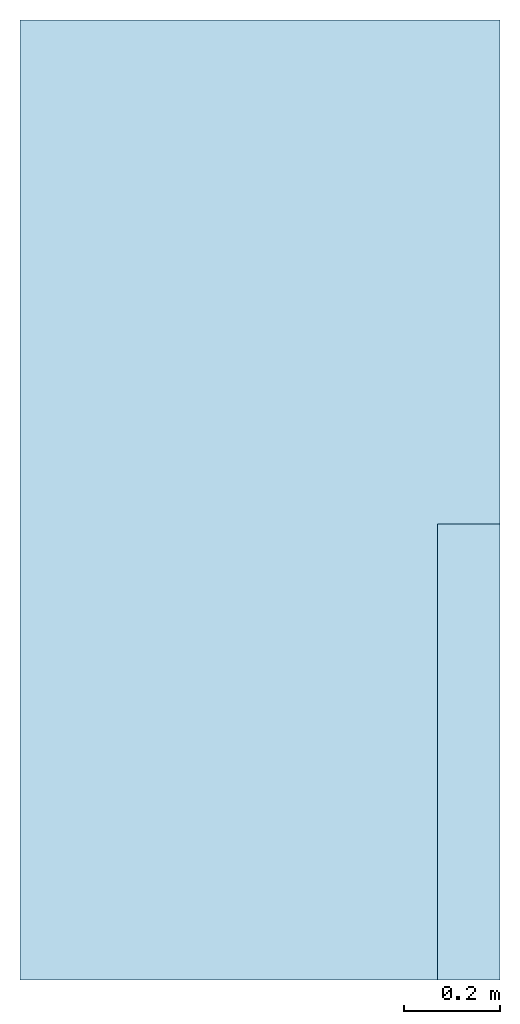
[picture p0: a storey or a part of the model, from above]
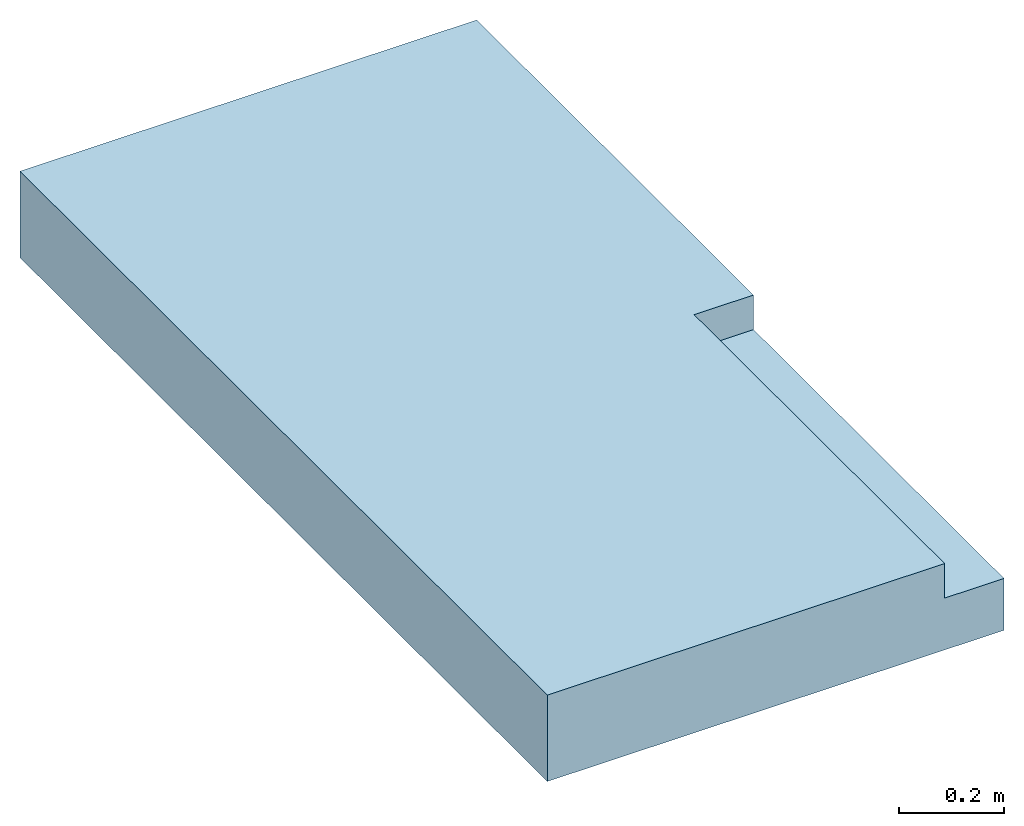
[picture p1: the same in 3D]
Properties of the parts of a building model (IFC4)

# File
Description: no view
File name: ÖBV_OEBV_Richtlinie_Treppe.ifc
Time: 2024-03-13T09:45:26
Author: Mikko Stachl
Organization: Oesterreichische Bautechnik Vereinigung
Written by: OEBV
Made in: ODA SDAI 24.5

# IfcSite, Liegenschaft
RefLatitude: 48, 8, 10, 320000; RefLongitude: 11, 41, 19, 320000

# IfcBuildingStorey (2)
In: Gebäude
Elevation: 0 m
Name
Geschoss 01
Geschoss 02

# IfcBuildingElementProxy (8)
In: Geschoss 02
Name | Allright_Bauteil_ID
macro | 0065Mak0000000005
macro | 0065Mak0000000010
macro | 0065Mak0000000015
macro | 0065Mak0000000020
macro | 0065Mak0000000025
macro | 0065Mak0000000030
 | 0065Mak0000000035
macro | 0065Mak0000000040

# IfcElementAssembly (8)
In: Geschoss 02
Name | Allright_Bauteil_ID
SpatialDim_Group | 0065Elg0000000006
SpatialDim_Group | 0065Elg0000000011
SpatialDim_Group | 0065Elg0000000016
SpatialDim_Group | 0065Elg0000000021
SpatialDim_Group | 0065Elg0000000026
SpatialDim_Group | 0065Elg0000000031
SpatialDim_Group | 0065Elg0000000036
SpatialDim_Group | 0065Elg0000000041

# IfcSlab (2)
Name | In | Allright_Bauteil_ID
 | Geschoss 01 | 0015ErE0000000004
 | Geschoss 02 | 0065ErE0000000042

# IfcStair, Treppe
In: Geschoss 02
PredefinedType: STRAIGHT_RUN_STAIR
AllplanAttributes - Allright_Bauteil_ID: 0065Tre0000000044
